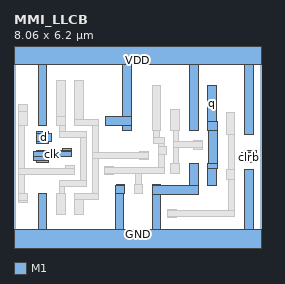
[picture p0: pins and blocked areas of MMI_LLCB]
MACRO MMI_LLCB
	CLASS CORE ;
	FOREIGN MMI_LLCB 0 0 ;
	SIZE 8.06 BY 6.2 ;
	SYMMETRY X Y ;
	SITE CORE1 ;
	PIN d
		DIRECTION input ;
		USE SIGNAL ;
		PORT
			LAYER M1 ;
			RECT 0.74 3.545 1.12 3.6 ;
			LAYER M1 ;
			RECT 0.74 3.265 1.235 3.545 ;
			LAYER M1 ;
			RECT 0.74 3.22 1.12 3.265 ;
		END
		AntennaGateArea 0.3465 ;
	END d
	PIN GND
		DIRECTION inout ;
		USE GROUND ;
		PORT
			LAYER M1 ;
			RECT 3.33 1.85 3.61 1.885 ;
			LAYER M1 ;
			RECT 0.795 0.42 1.075 1.595 ;
			LAYER M1 ;
			RECT 3.3 1.57 3.61 1.85 ;
			LAYER M1 ;
			RECT 4.51 1.84 4.79 1.885 ;
			LAYER M1 ;
			RECT 5.74 1.84 6.02 2.56 ;
			LAYER M1 ;
			RECT 3.3 0.42 3.58 1.57 ;
			LAYER M1 ;
			RECT 4.51 1.56 6.02 1.84 ;
			LAYER M1 ;
			RECT 4.51 0.42 4.79 1.56 ;
			LAYER M1 ;
			RECT 7.52 0.42 7.8 2.355 ;
			LAYER M1 ;
			RECT 0 -0.42 8.06 0.42 ;
		END
	END GND
	PIN q
		DIRECTION output ;
		USE SIGNAL ;
		PORT
			LAYER M1 ;
			RECT 6.33 3.92 6.61 5.105 ;
			LAYER M1 ;
			RECT 6.33 3.635 6.635 3.92 ;
			LAYER M1 ;
			RECT 6.35 2.56 6.635 3.635 ;
			LAYER M1 ;
			RECT 6.33 2.41 6.635 2.56 ;
			LAYER M1 ;
			RECT 6.33 1.86 6.61 2.41 ;
		END
		AntennaDiffArea 0.91245 ;
	END q
	PIN VDD
		DIRECTION inout ;
		USE POWER ;
		PORT
			LAYER M1 ;
			RECT 0 5.78 8.06 6.62 ;
			LAYER M1 ;
			RECT 0.795 3.8 1.075 5.78 ;
			LAYER M1 ;
			RECT 3.55 4.085 3.83 5.78 ;
			LAYER M1 ;
			RECT 2.99 3.8 3.83 4.085 ;
			LAYER M1 ;
			RECT 3.55 3.635 3.83 3.8 ;
			LAYER M1 ;
			RECT 5.74 3.635 6.02 5.78 ;
			LAYER M1 ;
			RECT 7.52 3.52 7.8 5.78 ;
		END
	END VDD
	PIN clk
		DIRECTION input ;
		USE CLOCK ;
		PORT
			LAYER M1 ;
			RECT 1.595 2.98 1.875 3.065 ;
			LAYER M1 ;
			RECT 0.74 2.94 1.875 2.98 ;
			LAYER M1 ;
			RECT 0.62 2.785 1.875 2.94 ;
			LAYER M1 ;
			RECT 0.62 2.66 1.12 2.785 ;
			LAYER M1 ;
			RECT 0.74 2.6 1.12 2.66 ;
		END
		AntennaGateArea 0.45675 ;
	END clk
	PIN clrb
		DIRECTION input ;
		USE SIGNAL ;
		PORT
			LAYER M1 ;
			RECT 7.535 2.905 7.915 2.985 ;
			LAYER M1 ;
			RECT 7.415 2.625 7.915 2.905 ;
			LAYER M1 ;
			RECT 7.535 2.61 7.915 2.625 ;
		END
		AntennaGateArea 0.17325 ;
	END clrb
	OBS
		LAYER M1 ;
		RECT 0.16 4.25 0.44 4.5 ;
		LAYER M1 ;
		RECT 0.15 3.8 0.44 4.25 ;
		LAYER M1 ;
		RECT 1.385 4.085 1.665 5.27 ;
		LAYER M1 ;
		RECT 1.385 3.8 1.675 4.085 ;
		LAYER M1 ;
		RECT 1.975 4 2.255 5.27 ;
		LAYER M1 ;
		RECT 1.975 3.805 2.76 4 ;
		LAYER M1 ;
		RECT 1.975 3.8 2.255 3.805 ;
		LAYER M1 ;
		RECT 0.15 2.4 0.345 3.8 ;
		LAYER M1 ;
		RECT 1.485 3.6 1.675 3.8 ;
		LAYER M1 ;
		RECT 1.485 3.405 2.37 3.6 ;
		LAYER M1 ;
		RECT 1.695 2.4 1.975 2.485 ;
		LAYER M1 ;
		RECT 0.15 2.205 1.975 2.4 ;
		LAYER M1 ;
		RECT 0.15 1.595 0.345 2.205 ;
		LAYER M1 ;
		RECT 2.18 2.005 2.37 3.405 ;
		LAYER M1 ;
		RECT 1.47 1.81 2.37 2.005 ;
		LAYER M1 ;
		RECT 2.57 2.91 2.76 3.805 ;
		LAYER M1 ;
		RECT 4.51 3.635 4.79 5.105 ;
		LAYER M1 ;
		RECT 5.105 3.635 5.385 4.335 ;
		LAYER M1 ;
		RECT 4.545 3.415 4.74 3.635 ;
		LAYER M1 ;
		RECT 4.545 3.22 4.9 3.415 ;
		LAYER M1 ;
		RECT 4.705 3.13 4.9 3.22 ;
		LAYER M1 ;
		RECT 5.19 3.275 5.38 3.635 ;
		LAYER M1 ;
		RECT 5.87 3.275 6.15 3.31 ;
		LAYER M1 ;
		RECT 4.1 2.91 4.38 2.96 ;
		LAYER M1 ;
		RECT 2.57 2.715 4.38 2.91 ;
		LAYER M1 ;
		RECT 1.47 1.595 1.66 1.81 ;
		LAYER M1 ;
		RECT 0.15 1.365 0.44 1.595 ;
		LAYER M1 ;
		RECT 0.16 1.28 0.44 1.365 ;
		LAYER M1 ;
		RECT 1.385 0.895 1.665 1.595 ;
		LAYER M1 ;
		RECT 1.975 1.57 2.255 1.595 ;
		LAYER M1 ;
		RECT 2.57 1.57 2.76 2.715 ;
		LAYER M1 ;
		RECT 4.1 2.68 4.38 2.715 ;
		LAYER M1 ;
		RECT 4.705 2.85 4.99 3.13 ;
		LAYER M1 ;
		RECT 5.19 3.085 6.15 3.275 ;
		LAYER M1 ;
		RECT 2.96 2.42 3.24 2.48 ;
		LAYER M1 ;
		RECT 4.705 2.42 4.9 2.85 ;
		LAYER M1 ;
		RECT 5.19 2.565 5.38 3.085 ;
		LAYER M1 ;
		RECT 5.87 3.03 6.15 3.085 ;
		LAYER M1 ;
		RECT 2.96 2.23 4.9 2.42 ;
		LAYER M1 ;
		RECT 5.105 2.25 5.385 2.565 ;
		LAYER M1 ;
		RECT 6.93 3.52 7.21 4.22 ;
		LAYER M1 ;
		RECT 2.96 2.2 3.24 2.23 ;
		LAYER M1 ;
		RECT 3.95 1.885 4.145 2.23 ;
		LAYER M1 ;
		RECT 1.975 1.38 2.76 1.57 ;
		LAYER M1 ;
		RECT 3.92 1.57 4.2 1.885 ;
		LAYER M1 ;
		RECT 7.015 2.355 7.205 3.52 ;
		LAYER M1 ;
		RECT 6.93 2.04 7.21 2.355 ;
		LAYER M1 ;
		RECT 1.975 0.895 2.255 1.38 ;
		LAYER M1 ;
		RECT 5.02 1.035 5.3 1.065 ;
		LAYER M1 ;
		RECT 5.02 1.02 5.305 1.035 ;
		LAYER M1 ;
		RECT 7.015 1.02 7.205 2.04 ;
		LAYER M1 ;
		RECT 5.02 0.83 7.205 1.02 ;
		LAYER M1 ;
		RECT 5.02 0.785 5.3 0.83 ;
	END
END MMI_LLCB
